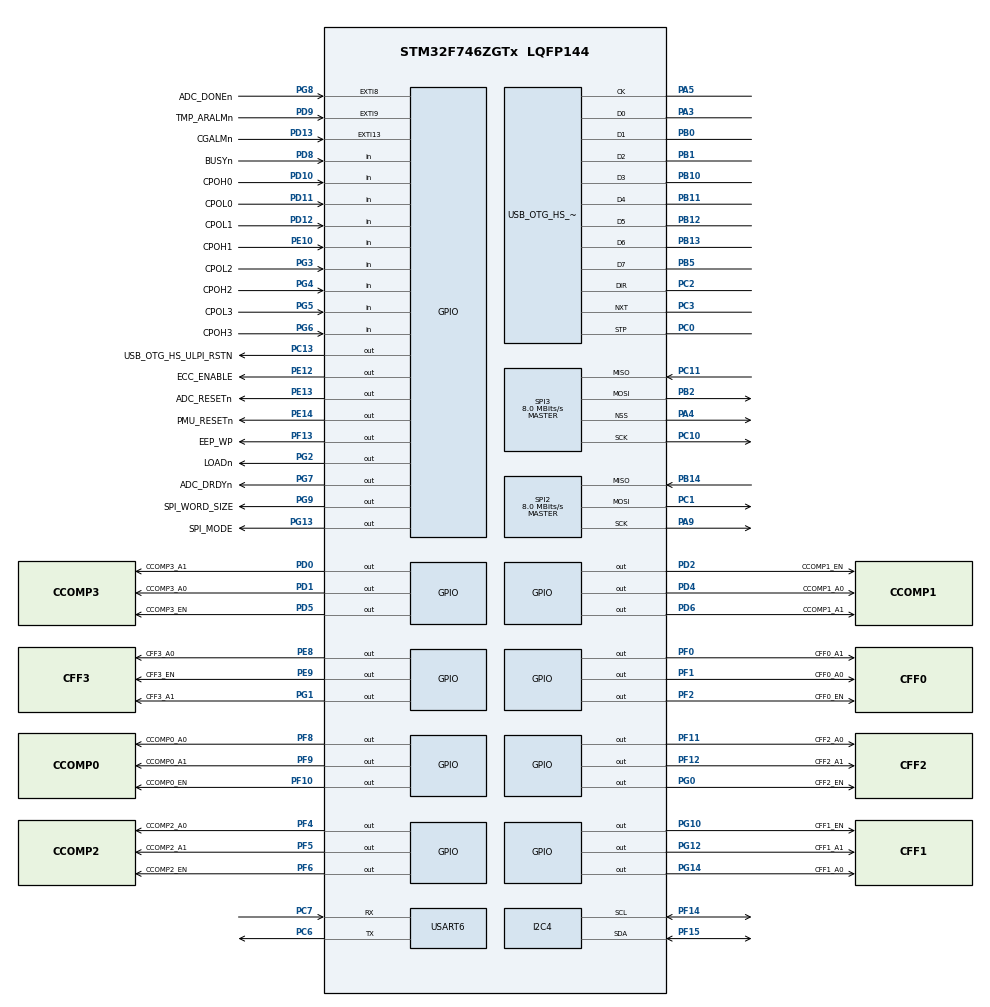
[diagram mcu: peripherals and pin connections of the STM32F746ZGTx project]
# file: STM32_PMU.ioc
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CORTEX_M7.default_mode_Activation=1
FREERTOS.Queues01=uartQueue,4,PMU_Data_t,0,Dynamic,NULL,NULL;usbRxQueue,128,uint8_t,0,Dynamic,NULL,NULL;pmuCmdQueue,8,16,1,Dynamic,NULL,NULL
FREERTOS.Tasks01=PMU_Task,24,512,StartPMU_Task,Default,NULL,Dynamic,NULL,NULL;commandTask,24,512,StartCommandTask,Default,NULL,Dynamic,NULL,NULL;uartLoggingTask,8,512,StartUartLoggingTask,Default,NULL,Dynamic,NULL,NULL;ADC_Task,32,256,StartADC_Task,Default,NULL,Dynamic,NULL,NULL
FREERTOS.configUSE_NEWLIB_REENTRANT=1
Mcu.Family=STM32F7
Mcu.Name=STM32F746ZGTx
Mcu.Package=LQFP144
NVIC.EXTI15_10_IRQn=true\:5\:0\:false\:false\:true\:true\:true\:true\:true
NVIC.EXTI9_5_IRQn=true\:5\:0\:false\:false\:true\:true\:true\:true\:true
NVIC.OTG_HS_IRQn=true\:5\:0\:false\:false\:true\:true\:false\:true\:true
NVIC.PriorityGroup=NVIC_PRIORITYGROUP_4
NVIC.TIM1_UP_TIM10_IRQn=true\:15\:0\:false\:false\:true\:false\:false\:true\:true
NVIC.TimeBase=TIM1_UP_TIM10_IRQn
NVIC.TimeBaseIP=TIM1
PA13.Mode=Trace_Synchro_4bits_JTAG
PA13.Signal=SYS_JTMS-SWDIO
PA14.Mode=Trace_Synchro_4bits_JTAG
PA14.Signal=SYS_JTCK-SWCLK
PA15.Mode=Trace_Synchro_4bits_JTAG
PA15.Signal=SYS_JTDI
PA3.Mode=Device_HS
PA3.Signal=USB_OTG_HS_ULPI_D0
PA4.Mode=NSS_Signal_Hard_Output
PA4.Signal=SPI3_NSS
PA5.Mode=Device_HS
PA5.Signal=USB_OTG_HS_ULPI_CK
PA9.Mode=Full_Duplex_Master
PA9.Signal=SPI2_SCK
PB0.Mode=Device_HS
PB0.Signal=USB_OTG_HS_ULPI_D1
PB1.Mode=Device_HS
PB1.Signal=USB_OTG_HS_ULPI_D2
PB10.Mode=Device_HS
PB10.Signal=USB_OTG_HS_ULPI_D3
PB11.Mode=Device_HS
PB11.Signal=USB_OTG_HS_ULPI_D4
PB12.Mode=Device_HS
PB12.Signal=USB_OTG_HS_ULPI_D5
PB13.Mode=Device_HS
PB13.Signal=USB_OTG_HS_ULPI_D6
PB14.Mode=Full_Duplex_Master
PB14.Signal=SPI2_MISO
PB2.Mode=Full_Duplex_Master
PB2.Signal=SPI3_MOSI
PB3.Mode=Trace_Synchro_4bits_JTAG
PB3.Signal=SYS_JTDO-SWO
PB5.Mode=Device_HS
PB5.Signal=USB_OTG_HS_ULPI_D7
PB9.Signal=SPI2_NSS
PC0.Mode=Device_HS
PC0.Signal=USB_OTG_HS_ULPI_STP
PC1.Mode=Full_Duplex_Master
PC1.Signal=SPI2_MOSI
PC10.Mode=Full_Duplex_Master
PC10.Signal=SPI3_SCK
PC11.Mode=Full_Duplex_Master
PC11.Signal=SPI3_MISO
PC13.GPIO_Label=USB_OTG_HS_ULPI_RSTN 
PC13.PinState=GPIO_PIN_SET
PC13.Signal=GPIO_Output
PC2.Mode=Device_HS
PC2.Signal=USB_OTG_HS_ULPI_DIR
PC3.Mode=Device_HS
PC3.Signal=USB_OTG_HS_ULPI_NXT
PC6.Mode=Asynchronous
PC6.Signal=USART6_TX
PC7.Mode=Asynchronous
PC7.Signal=USART6_RX
PD0.GPIO_Label=CCOMP3_A1
PD0.Signal=GPIO_Output
PD1.GPIO_Label=CCOMP3_A0
PD1.Signal=GPIO_Output
PD10.GPIO_Label=CPOH0
PD10.Signal=GPIO_Input
PD11.GPIO_Label=CPOL0
PD11.Signal=GPIO_Input
PD12.GPIO_Label=CPOL1
PD12.Signal=GPIO_Input
PD13.GPIO_Label=CGALMn
PD13.Signal=GPXTI13
PD2.GPIO_Label=CCOMP1_EN
PD2.Signal=GPIO_Output
PD4.GPIO_Label=CCOMP1_A0
PD4.Signal=GPIO_Output
PD5.GPIO_Label=CCOMP3_EN
PD5.Signal=GPIO_Output
PD6.GPIO_Label=CCOMP1_A1
PD6.Signal=GPIO_Output
PD8.GPIO_Label=BUSYn
PD8.Signal=GPIO_Input
PD9.GPIO_Label=TMP_ARALMn
PD9.Signal=GPXTI9
PE10.GPIO_Label=CPOH1
PE10.Signal=GPIO_Input
PE12.GPIO_Label=ECC_ENABLE
PE12.PinState=GPIO_PIN_SET
PE12.Signal=GPIO_Output
PE13.GPIO_Label=ADC_RESETn
PE13.PinState=GPIO_PIN_RESET
PE13.Signal=GPIO_Output
PE14.GPIO_Label=PMU_RESETn
PE14.PinState=GPIO_PIN_SET
PE14.Signal=GPIO_Output
PE2.Mode=Trace_Synchro_4bits_JTAG
PE2.Signal=SYS_TRACECLK
PE3.Mode=Trace_Synchro_4bits_JTAG
PE3.Signal=SYS_TRACED0
PE4.Mode=Trace_Synchro_4bits_JTAG
PE4.Signal=SYS_TRACED1
PE5.Mode=Trace_Synchro_4bits_JTAG
PE5.Signal=SYS_TRACED2
PE6.Mode=Trace_Synchro_4bits_JTAG
PE6.Signal=SYS_TRACED3
PE8.GPIO_Label=CFF3_A0
PE8.Signal=GPIO_Output
PE9.GPIO_Label=CFF3_EN
PE9.Signal=GPIO_Output
PF0.GPIO_Label=CFF0_A1
PF0.Signal=GPIO_Output
PF1.GPIO_Label=CFF0_A0
PF1.Signal=GPIO_Output
PF10.GPIO_Label=CCOMP0_EN
PF10.Signal=GPIO_Output
PF11.GPIO_Label=CFF2_A0
PF11.Signal=GPIO_Output
PF12.GPIO_Label=CFF2_A1
PF12.Signal=GPIO_Output
PF13.GPIO_Label=EEP_WP
PF13.PinState=GPIO_PIN_SET
PF13.Signal=GPIO_Output
PF14.Mode=I2C
PF14.Signal=I2C4_SCL
PF15.Mode=I2C
PF15.Signal=I2C4_SDA
PF2.GPIO_Label=CFF0_EN
PF2.Signal=GPIO_Output
PF4.GPIO_Label=CCOMP2_A0
PF4.Signal=GPIO_Output
PF5.GPIO_Label=CCOMP2_A1
PF5.Signal=GPIO_Output
PF6.GPIO_Label=CCOMP2_EN
PF6.Signal=GPIO_Output
PF8.GPIO_Label=CCOMP0_A0
PF8.Signal=GPIO_Output
PF9.GPIO_Label=CCOMP0_A1
PF9.Signal=GPIO_Output
PG0.GPIO_Label=CFF2_EN
PG0.Signal=GPIO_Output
PG1.GPIO_Label=CFF3_A1
PG1.Signal=GPIO_Output
PG10.GPIO_Label=CFF1_EN
PG10.Signal=GPIO_Output
PG12.GPIO_Label=CFF1_A1
PG12.Signal=GPIO_Output
PG13.GPIO_Label=SPI_MODE
PG13.Signal=GPIO_Output
PG14.GPIO_Label=CFF1_A0
PG14.Signal=GPIO_Output
PG2.GPIO_Label=LOADn
PG2.PinState=GPIO_PIN_SET
PG2.Signal=GPIO_Output
PG3.GPIO_Label=CPOL2
PG3.Signal=GPIO_Input
PG4.GPIO_Label=CPOH2
PG4.Signal=GPIO_Input
PG5.GPIO_Label=CPOL3
PG5.Signal=GPIO_Input
PG6.GPIO_Label=CPOH3
PG6.Signal=GPIO_Input
PG7.GPIO_Label=ADC_DRDYn
PG7.Signal=GPIO_Output
PG8.GPIO_Label=ADC_DONEn
PG8.Signal=GPXTI8
PG9.GPIO_Label=SPI_WORD_SIZE
PG9.Signal=GPIO_Output
PH0/OSC_IN.Mode=HSE-External-Clock-Source
PH0/OSC_IN.Signal=RCC_OSC_IN
PH1/OSC_OUT.Mode=HSE-External-Clock-Source
PH1/OSC_OUT.Signal=RCC_OSC_OUT
ProjectManager.HeapSize=0x200
ProjectManager.StackSize=0x400
ProjectManager.TargetToolchain=STM32CubeIDE
RCC.AHBFreq_Value=64000000
RCC.APB1CLKDivider=RCC_HCLK_DIV4
RCC.APB1Freq_Value=16000000
RCC.APB1TimFreq_Value=32000000
RCC.APB2CLKDivider=RCC_HCLK_DIV2
RCC.APB2Freq_Value=32000000
RCC.APB2TimFreq_Value=64000000
RCC.CortexFreq_Value=64000000
RCC.HCLKFreq_Value=64000000
RCC.HSE_VALUE=8000000
RCC.HSI_VALUE=16000000
RCC.LSE_VALUE=32768
RCC.PLLM=8
RCC.PLLN=128
RCC.PLLSourceVirtual=RCC_PLLSOURCE_HSE
RCC.SYSCLKFreq_VALUE=64000000
RCC.SYSCLKSource=RCC_SYSCLKSOURCE_PLLCLK
RCC.USBFreq_Value=64000000
RCC.VCOOutputFreq_Value=128000000
SPI2.BaudRatePrescaler=SPI_BAUDRATEPRESCALER_2
SPI2.CalculateBaudRate=8.0 MBits/s
SPI2.Direction=SPI_DIRECTION_2LINES
SPI2.Mode=SPI_MODE_MASTER
SPI2.VirtualType=VM_MASTER
SPI3.BaudRatePrescaler=SPI_BAUDRATEPRESCALER_2
SPI3.CLKPhase=SPI_PHASE_2EDGE
SPI3.CLKPolarity=SPI_POLARITY_LOW
SPI3.CalculateBaudRate=8.0 MBits/s
SPI3.Direction=SPI_DIRECTION_2LINES
SPI3.Mode=SPI_MODE_MASTER
SPI3.VirtualNSS=VM_NSSHARD
SPI3.VirtualType=VM_MASTER
USART6.VirtualMode-Asynchronous=VM_ASYNC
USB_DEVICE.CLASS_NAME_HS=CDC
USB_DEVICE.VirtualMode-CDC_HS=Cdc
USB_DEVICE.VirtualModeHS=Cdc_HS
USB_OTG_HS.VirtualMode-Device_HS=Device_HS
VP_FREERTOS_VS_CMSIS_V2.Mode=CMSIS_V2
VP_SYS_VS_tim1.Mode=TIM1
VP_USB_DEVICE_VS_USB_DEVICE_CDC_HS.Mode=CDC_HS
board=custom

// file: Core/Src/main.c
/* USER CODE BEGIN Header */
/**
  ******************************************************************************
  * @file           : main.c
  * @brief          : Main program body
  ******************************************************************************
  * @attention
  *
  * Copyright (c) 2026 STMicroelectronics.
  * All rights reserved.
  *
  * This software is licensed under terms that can be found in the LICENSE file
  * in the root directory of this software component.
  * If no LICENSE file comes with this software, it is provided AS-IS.
  *
  ******************************************************************************
  */
/* USER CODE END Header */
#include "main.h"
#include "cmsis_os.h"
#include "i2c.h"
#include "spi.h"
#include "usart.h"
#include "usb_device.h"
#include "gpio.h"

void SystemClock_Config(void);
static void MPU_Config(void);
void MX_FREERTOS_Init(void);

int main(void)
{

  /* MPU Configuration--------------------------------------------------------*/
  MPU_Config();

  /* MCU Configuration--------------------------------------------------------*/

  /* Reset of all peripherals, Initializes the Flash interface and the Systick. */
  HAL_Init();

  /* Configure the system clock */
  SystemClock_Config();

  /* Initialize all configured peripherals */
  MX_GPIO_Init();
  MX_I2C4_Init();
  MX_SPI2_Init();
  MX_SPI3_Init();
  MX_USART6_UART_Init();

  /* Init scheduler */
  osKernelInitialize();  /* Call init function for freertos objects (in cmsis_os2.c) */
  MX_FREERTOS_Init();

  /* Start scheduler */
  osKernelStart();

  /* We should never get here as control is now taken by the scheduler */

  /* Infinite loop */
  while (1)
  {

  }
}

void SystemClock_Config(void)
{
  RCC_OscInitTypeDef RCC_OscInitStruct = {0};
  RCC_ClkInitTypeDef RCC_ClkInitStruct = {0};

  /** Configure the main internal regulator output voltage
  */
  __HAL_RCC_PWR_CLK_ENABLE();
  __HAL_PWR_VOLTAGESCALING_CONFIG(PWR_REGULATOR_VOLTAGE_SCALE1);

  /** Initializes the RCC Oscillators according to the specified parameters
  * in the RCC_OscInitTypeDef structure.
  */
  RCC_OscInitStruct.OscillatorType = RCC_OSCILLATORTYPE_HSI;
  RCC_OscInitStruct.HSIState = RCC_HSI_ON;
  RCC_OscInitStruct.HSICalibrationValue = RCC_HSICALIBRATION_DEFAULT;
  RCC_OscInitStruct.PLL.PLLState = RCC_PLL_ON;
  RCC_OscInitStruct.PLL.PLLSource = RCC_PLLSOURCE_HSI;
  RCC_OscInitStruct.PLL.PLLM = 8;
  RCC_OscInitStruct.PLL.PLLN = 192;
  RCC_OscInitStruct.PLL.PLLP = RCC_PLLP_DIV2;
  RCC_OscInitStruct.PLL.PLLQ = 2;
  if (HAL_RCC_OscConfig(&RCC_OscInitStruct) != HAL_OK)
  {
    Error_Handler();
  }

  /** Activate the Over-Drive mode
  */
  if (HAL_PWREx_EnableOverDrive() != HAL_OK)
  {
    Error_Handler();
  }

  /** Initializes the CPU, AHB and APB buses clocks
  */
  RCC_ClkInitStruct.ClockType = RCC_CLOCKTYPE_HCLK|RCC_CLOCKTYPE_SYSCLK
                              |RCC_CLOCKTYPE_PCLK1|RCC_CLOCKTYPE_PCLK2;
  RCC_ClkInitStruct.SYSCLKSource = RCC_SYSCLKSOURCE_PLLCLK;
  RCC_ClkInitStruct.AHBCLKDivider = RCC_SYSCLK_DIV1;
  RCC_ClkInitStruct.APB1CLKDivider = RCC_HCLK_DIV4;
  RCC_ClkInitStruct.APB2CLKDivider = RCC_HCLK_DIV2;

  if (HAL_RCC_ClockConfig(&RCC_ClkInitStruct, FLASH_LATENCY_6) != HAL_OK)
  {
    Error_Handler();
  }
}

 /* MPU Configuration */

void MPU_Config(void)
{
  MPU_Region_InitTypeDef MPU_InitStruct = {0};

  /* Disables the MPU */
  HAL_MPU_Disable();

  /** Initializes and configures the Region and the memory to be protected
  */
  MPU_InitStruct.Enable = MPU_REGION_ENABLE;
  MPU_InitStruct.Number = MPU_REGION_NUMBER0;
  MPU_InitStruct.BaseAddress = 0x0;
  MPU_InitStruct.Size = MPU_REGION_SIZE_4GB;
  MPU_InitStruct.SubRegionDisable = 0x87;
  MPU_InitStruct.TypeExtField = MPU_TEX_LEVEL0;
  MPU_InitStruct.AccessPermission = MPU_REGION_NO_ACCESS;
  MPU_InitStruct.DisableExec = MPU_INSTRUCTION_ACCESS_DISABLE;
  MPU_InitStruct.IsShareable = MPU_ACCESS_SHAREABLE;
  MPU_InitStruct.IsCacheable = MPU_ACCESS_NOT_CACHEABLE;
  MPU_InitStruct.IsBufferable = MPU_ACCESS_NOT_BUFFERABLE;

  HAL_MPU_ConfigRegion(&MPU_InitStruct);
  /* Enables the MPU */
  HAL_MPU_Enable(MPU_PRIVILEGED_DEFAULT);

}

void HAL_TIM_PeriodElapsedCallback(TIM_HandleTypeDef *htim)
{
  if (htim->Instance == TIM1)
  {
    HAL_IncTick();
  }
}

void Error_Handler(void)
{
  __disable_irq();
  while (1)
  {
  }
}

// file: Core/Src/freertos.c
/* USER CODE BEGIN Header */
/**
  ******************************************************************************
  * File Name          : freertos.c
  * Description        : Code for freertos applications
  ******************************************************************************
  * @attention
  *
  * Copyright (c) 2026 STMicroelectronics.
  * All rights reserved.
  *
  * This software is licensed under terms that can be found in the LICENSE file
  * in the root directory of this software component.
  * If no LICENSE file comes with this software, it is provided AS-IS.
  *
  ******************************************************************************
  */
/* USER CODE END Header */

#include "FreeRTOS.h"
#include "task.h"
#include "main.h"
#include "cmsis_os.h"

/* Definitions for defaultTask */
osThreadId_t defaultTaskHandle;
const osThreadAttr_t defaultTask_attributes = {
  .name = "defaultTask",
  .stack_size = 256 * 4,
  .priority = (osPriority_t) osPriorityAboveNormal,
};
/* Definitions for commandTask */
osThreadId_t commandTaskHandle;
const osThreadAttr_t commandTask_attributes = {
  .name = "commandTask",
  .stack_size = 512 * 4,
  .priority = (osPriority_t) osPriorityNormal,
};
/* Definitions for uartLoggingTask */
osThreadId_t uartLoggingTaskHandle;
const osThreadAttr_t uartLoggingTask_attributes = {
  .name = "uartLoggingTask",
  .stack_size = 512 * 4,
  .priority = (osPriority_t) osPriorityLow,
};
/* Definitions for uartQueue */
osMessageQueueId_t uartQueueHandle;
const osMessageQueueAttr_t uartQueue_attributes = {
  .name = "uartQueue"
};
/* Definitions for usbRxQueue */
osMessageQueueId_t usbRxQueueHandle;
const osMessageQueueAttr_t usbRxQueue_attributes = {
  .name = "usbRxQueue"
};

void StartDefaultTask(void *argument);
void StartCommandTask(void *argument);
void StartUartLoggingTask(void *argument);

extern void MX_USB_DEVICE_Init(void);
void MX_FREERTOS_Init(void); /* (MISRA C 2004 rule 8.1) */

void MX_FREERTOS_Init(void) {

  /* Create the queue(s) */
  /* creation of uartQueue */
  uartQueueHandle = osMessageQueueNew (4, sizeof(PMU_Data_t), &uartQueue_attributes);

  /* creation of usbRxQueue */
  usbRxQueueHandle = osMessageQueueNew (128, sizeof(uint8_t), &usbRxQueue_attributes);

  /* Create the thread(s) */
  /* creation of defaultTask */
  defaultTaskHandle = osThreadNew(StartDefaultTask, NULL, &defaultTask_attributes);

  /* creation of commandTask */
  commandTaskHandle = osThreadNew(StartCommandTask, NULL, &commandTask_attributes);

  /* creation of uartLoggingTask */
  uartLoggingTaskHandle = osThreadNew(StartUartLoggingTask, NULL, &uartLoggingTask_attributes);

}

void StartDefaultTask(void *argument)
{
  /* init code for USB_DEVICE */
  MX_USB_DEVICE_Init();
  for(;;)
  {
    osDelay(1);
  }
}

void StartCommandTask(void *argument)
{
  for(;;)
  {
    osDelay(1);
  }
}

void StartUartLoggingTask(void *argument)
{
  for(;;)
  {
    osDelay(1);
  }
}
